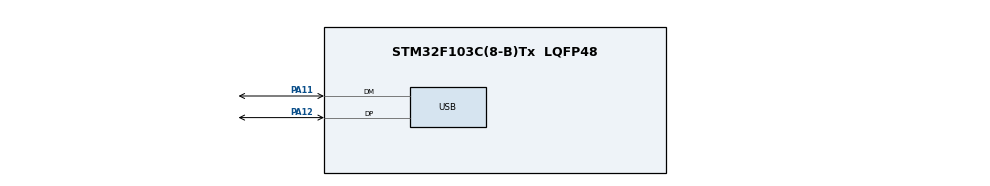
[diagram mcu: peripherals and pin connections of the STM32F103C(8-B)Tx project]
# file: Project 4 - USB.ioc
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Mcu.Family=STM32F1
Mcu.Name=STM32F103C(8-B)Tx
Mcu.Package=LQFP48
NVIC.PriorityGroup=NVIC_PRIORITYGROUP_4
NVIC.USB_LP_CAN1_RX0_IRQn=true\:0\:0\:false\:false\:true\:false\:true
PA11.Mode=Device
PA11.Signal=USB_DM
PA12.Mode=Device
PA12.Signal=USB_DP
PA13.Mode=Serial_Wire
PA13.Signal=SYS_JTMS-SWDIO
PA14.Mode=Serial_Wire
PA14.Signal=SYS_JTCK-SWCLK
PD0-OSC_IN.Mode=HSE-External-Oscillator
PD0-OSC_IN.Signal=RCC_OSC_IN
PD1-OSC_OUT.Mode=HSE-External-Oscillator
PD1-OSC_OUT.Signal=RCC_OSC_OUT
ProjectManager.HeapSize=0x200
ProjectManager.StackSize=0x400
ProjectManager.TargetToolchain=STM32CubeIDE
RCC.AHBFreq_Value=72000000
RCC.APB1CLKDivider=RCC_HCLK_DIV2
RCC.APB1Freq_Value=36000000
RCC.APB1TimFreq_Value=72000000
RCC.APB2Freq_Value=72000000
RCC.APB2TimFreq_Value=72000000
RCC.HCLKFreq_Value=72000000
RCC.PLLMUL=RCC_PLL_MUL9
RCC.PLLSourceVirtual=RCC_PLLSOURCE_HSE
RCC.SYSCLKFreq_VALUE=72000000
RCC.SYSCLKSource=RCC_SYSCLKSOURCE_PLLCLK
RCC.USBFreq_Value=48000000
RCC.USBPrescaler=RCC_USBCLKSOURCE_PLL_DIV1_5
USB_DEVICE.CLASS_NAME_FS=CDC
USB_DEVICE.VirtualMode=Cdc
USB_DEVICE.VirtualModeFS=Cdc_FS
VP_USB_DEVICE_VS_USB_DEVICE_CDC_FS.Mode=CDC_FS
board=custom

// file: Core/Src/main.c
/* USER CODE BEGIN Header */
/**
  ******************************************************************************
  * @file           : main.c
  * @brief          : Main program body
  ******************************************************************************
  * @attention
  *
  * <h2><center>&copy; Copyright (c) 2020 STMicroelectronics.
  * All rights reserved.</center></h2>
  *
  * This software component is licensed by ST under BSD 3-Clause license,
  * the "License"; You may not use this file except in compliance with the
  * License. You may obtain a copy of the License at:
  *                        opensource.org/licenses/BSD-3-Clause
  *
  ******************************************************************************
  */
/* USER CODE END Header */
#include "main.h"
#include "usb_device.h"

/* USER CODE BEGIN Includes */
#include "usbd_cdc_if.h"
#include <string.h>
/* USER CODE END Includes */

void SystemClock_Config(void);
static void MX_GPIO_Init(void);

/* USER CODE BEGIN 0 */

struct header {
	uint32_t msgno;
	uint32_t len;
};

#define BASE_ADDR 0x1000
#define COUNTER_REQ BASE_ADDR + 0x1
struct counter_req {
	struct header header;
};

#define COUNTER_RSP BASE_ADDR + 0x2
struct counter_rsp {
	struct header header;
	uint32_t value;
};

union usb_packets {
	struct header header;
	struct counter_req counter_req;
	struct counter_rsp counter_rsp;
};

int msg = 0;
union usb_packets usb_packet;
int usb_len;

/* just a counter */
int counter = 0;
static void usb_response(union usb_packets *packet, int len) {
	union usb_packets rsp;
	int sz = 0;

	if(len > sizeof(*packet)) return; /* wrong size */

	switch(packet->header.msgno) {
	case COUNTER_REQ:
		rsp.counter_rsp.header.msgno = COUNTER_RSP;
		rsp.counter_rsp.value = ++counter;
		sz = sizeof(rsp.counter_rsp);
		rsp.counter_req.header.len = sz;
		break;

	default:
		return;
	}
	CDC_Transmit_FS((uint8_t*)&rsp, sz);

}

/* USER CODE END 0 */

int main(void)
{

  /* MCU Configuration--------------------------------------------------------*/

  /* Reset of all peripherals, Initializes the Flash interface and the Systick. */
  HAL_Init();

  /* Configure the system clock */
  SystemClock_Config();

  /* Initialize all configured peripherals */
  MX_GPIO_Init();
  MX_USB_DEVICE_Init();

  /* Infinite loop */
  /* USER CODE BEGIN WHILE */
  while (1)
  {
	  if(msg) {
		  usb_response(&usb_packet, usb_len);
		  msg = 0;
//		  CDC_Transmit_FS(usb_buffer, usb_len);
	  }
//	  HAL_Delay(500);
    /* USER CODE END WHILE */

  }
}

void SystemClock_Config(void)
{
  RCC_OscInitTypeDef RCC_OscInitStruct = {0};
  RCC_ClkInitTypeDef RCC_ClkInitStruct = {0};
  RCC_PeriphCLKInitTypeDef PeriphClkInit = {0};

  /** Initializes the RCC Oscillators according to the specified parameters
  * in the RCC_OscInitTypeDef structure.
  */
  RCC_OscInitStruct.OscillatorType = RCC_OSCILLATORTYPE_HSE;
  RCC_OscInitStruct.HSEState = RCC_HSE_ON;
  RCC_OscInitStruct.HSEPredivValue = RCC_HSE_PREDIV_DIV1;
  RCC_OscInitStruct.HSIState = RCC_HSI_ON;
  RCC_OscInitStruct.PLL.PLLState = RCC_PLL_ON;
  RCC_OscInitStruct.PLL.PLLSource = RCC_PLLSOURCE_HSE;
  RCC_OscInitStruct.PLL.PLLMUL = RCC_PLL_MUL6;
  if (HAL_RCC_OscConfig(&RCC_OscInitStruct) != HAL_OK)
  {
    Error_Handler();
  }
  /** Initializes the CPU, AHB and APB buses clocks
  */
  RCC_ClkInitStruct.ClockType = RCC_CLOCKTYPE_HCLK|RCC_CLOCKTYPE_SYSCLK
                              |RCC_CLOCKTYPE_PCLK1|RCC_CLOCKTYPE_PCLK2;
  RCC_ClkInitStruct.SYSCLKSource = RCC_SYSCLKSOURCE_PLLCLK;
  RCC_ClkInitStruct.AHBCLKDivider = RCC_SYSCLK_DIV1;
  RCC_ClkInitStruct.APB1CLKDivider = RCC_HCLK_DIV2;
  RCC_ClkInitStruct.APB2CLKDivider = RCC_HCLK_DIV1;

  if (HAL_RCC_ClockConfig(&RCC_ClkInitStruct, FLASH_LATENCY_1) != HAL_OK)
  {
    Error_Handler();
  }
  PeriphClkInit.PeriphClockSelection = RCC_PERIPHCLK_USB;
  PeriphClkInit.UsbClockSelection = RCC_USBCLKSOURCE_PLL;
  if (HAL_RCCEx_PeriphCLKConfig(&PeriphClkInit) != HAL_OK)
  {
    Error_Handler();
  }
}

static void MX_GPIO_Init(void)
{

  /* GPIO Ports Clock Enable */
  __HAL_RCC_GPIOD_CLK_ENABLE();
  __HAL_RCC_GPIOA_CLK_ENABLE();

}

/* USER CODE BEGIN 4 */
void usb_recv(uint8_t* Buf, uint32_t *Len)
{
	/* if packet is too large */
	if(sizeof(usb_packet) < *Len) return;

	msg = 1;
	memcpy(&usb_packet, Buf, *Len);
	usb_len = *Len;

}
/* USER CODE END 4 */

void Error_Handler(void)
{
  __disable_irq();
  while (1)
  {
  }
}

/************************ (C) COPYRIGHT STMicroelectronics *****END OF FILE****/
